VERSION 5.7 ;
  NOWIREEXTENSIONATPIN ON ;
  DIVIDERCHAR "/" ;
  BUSBITCHARS "[]" ;
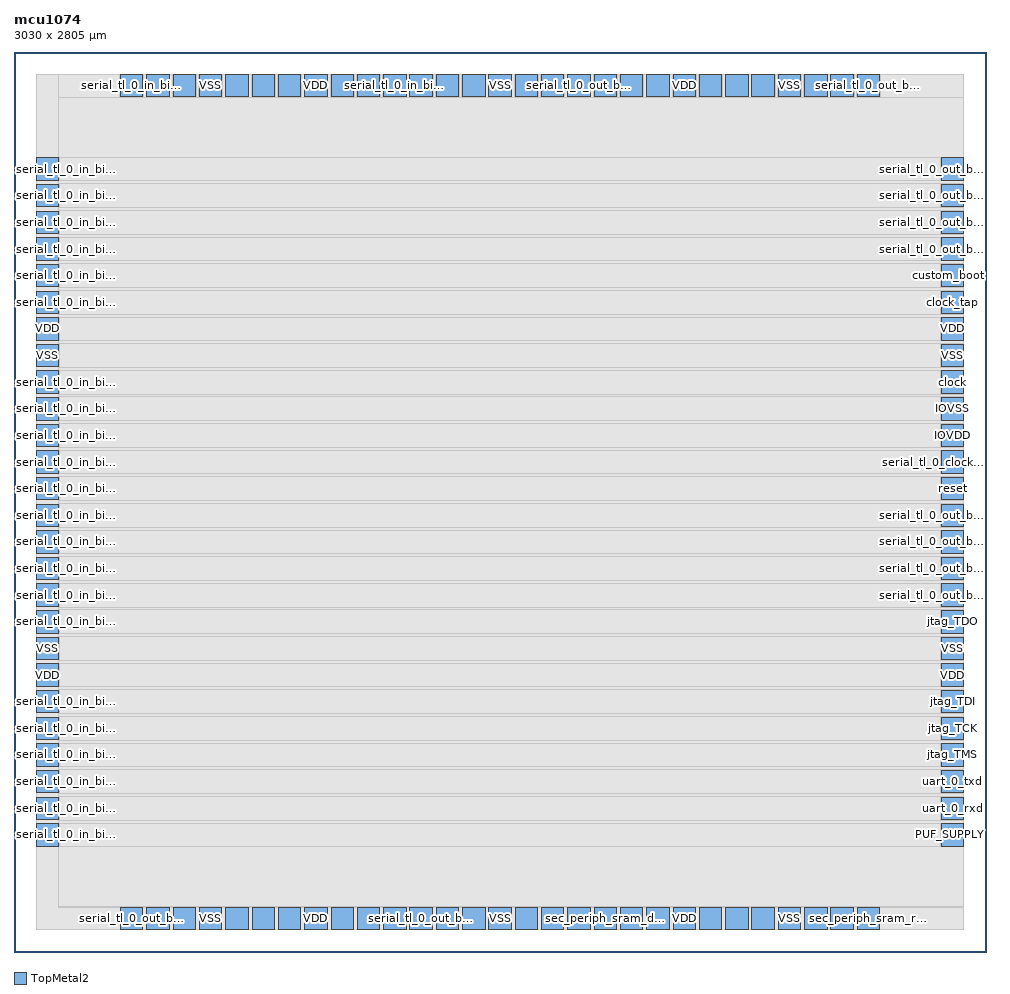
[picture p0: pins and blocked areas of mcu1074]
MACRO mcu1074
  CLASS BLOCK ;
  FOREIGN mcu1074 ;
  ORIGIN 0.000 0.000 ;
  SIZE 3030.000 BY 2805.000 ;
  PIN IOVDD
    DIRECTION INPUT ;
    USE POWER ;
    PORT
      LAYER TopMetal2 ;
        RECT 2890.000 1575.000 2960.000 1645.000 ;
    END
  END IOVDD
  PIN IOVSS
    DIRECTION INPUT ;
    USE GROUND ;
    PORT
      LAYER TopMetal2 ;
        RECT 2890.000 1658.000 2960.000 1728.000 ;
    END
  END IOVSS
  PIN PUF_SUPPLY
    DIRECTION INOUT ;
    USE POWER ;
    PORT
      LAYER TopMetal2 ;
        RECT 2890.000 330.000 2960.000 400.000 ;
    END
  END PUF_SUPPLY
  PIN VDD
    DIRECTION INPUT ;
    USE POWER ;
    PORT
      LAYER TopMetal2 ;
        RECT 70.000 1907.000 140.000 1977.000 ;
    END
  END VDD
  PIN VDD
    DIRECTION INPUT ;
    USE POWER ;
    PORT
      LAYER TopMetal2 ;
        RECT 70.000 828.000 140.000 898.000 ;
    END
  END VDD
  PIN VDD
    DIRECTION INPUT ;
    USE POWER ;
    PORT
      LAYER TopMetal2 ;
        RECT 2054.000 2665.000 2124.000 2735.000 ;
    END
  END VDD
  PIN VDD
    DIRECTION INPUT ;
    USE POWER ;
    PORT
      LAYER TopMetal2 ;
        RECT 906.000 2665.000 976.000 2735.000 ;
    END
  END VDD
  PIN VDD
    DIRECTION INPUT ;
    USE POWER ;
    PORT
      LAYER TopMetal2 ;
        RECT 2890.000 1907.000 2960.000 1977.000 ;
    END
  END VDD
  PIN VDD
    DIRECTION INPUT ;
    USE POWER ;
    PORT
      LAYER TopMetal2 ;
        RECT 2890.000 828.000 2960.000 898.000 ;
    END
  END VDD
  PIN VDD
    DIRECTION INPUT ;
    USE POWER ;
    PORT
      LAYER TopMetal2 ;
        RECT 2054.000 70.000 2124.000 140.000 ;
    END
  END VDD
  PIN VDD
    DIRECTION INPUT ;
    USE POWER ;
    PORT
      LAYER TopMetal2 ;
        RECT 906.000 70.000 976.000 140.000 ;
    END
  END VDD
  PIN VSS
    DIRECTION INPUT ;
    USE GROUND ;
    PORT
      LAYER TopMetal2 ;
        RECT 70.000 1824.000 140.000 1894.000 ;
    END
  END VSS
  PIN VSS
    DIRECTION INPUT ;
    USE GROUND ;
    PORT
      LAYER TopMetal2 ;
        RECT 70.000 911.000 140.000 981.000 ;
    END
  END VSS
  PIN VSS
    DIRECTION INPUT ;
    USE GROUND ;
    PORT
      LAYER TopMetal2 ;
        RECT 2382.000 2665.000 2452.000 2735.000 ;
    END
  END VSS
  PIN VSS
    DIRECTION INPUT ;
    USE GROUND ;
    PORT
      LAYER TopMetal2 ;
        RECT 1480.000 2665.000 1550.000 2735.000 ;
    END
  END VSS
  PIN VSS
    DIRECTION INPUT ;
    USE GROUND ;
    PORT
      LAYER TopMetal2 ;
        RECT 578.000 2665.000 648.000 2735.000 ;
    END
  END VSS
  PIN VSS
    DIRECTION INPUT ;
    USE GROUND ;
    PORT
      LAYER TopMetal2 ;
        RECT 2890.000 1824.000 2960.000 1894.000 ;
    END
  END VSS
  PIN VSS
    DIRECTION INPUT ;
    USE GROUND ;
    PORT
      LAYER TopMetal2 ;
        RECT 2890.000 911.000 2960.000 981.000 ;
    END
  END VSS
  PIN VSS
    DIRECTION INPUT ;
    USE GROUND ;
    PORT
      LAYER TopMetal2 ;
        RECT 2382.000 70.000 2452.000 140.000 ;
    END
  END VSS
  PIN VSS
    DIRECTION INPUT ;
    USE GROUND ;
    PORT
      LAYER TopMetal2 ;
        RECT 1480.000 70.000 1550.000 140.000 ;
    END
  END VSS
  PIN VSS
    DIRECTION INPUT ;
    USE GROUND ;
    PORT
      LAYER TopMetal2 ;
        RECT 578.000 70.000 648.000 140.000 ;
    END
  END VSS
  PIN clock
    DIRECTION INOUT ;
    USE SIGNAL ;
    ANTENNADIFFAREA 140.011200 ;
    PORT
      LAYER TopMetal2 ;
        RECT 2890.000 1741.000 2960.000 1811.000 ;
    END
  END clock
  PIN clock_tap
    DIRECTION INOUT ;
    USE SIGNAL ;
    ANTENNADIFFAREA 299.491180 ;
    PORT
      LAYER TopMetal2 ;
        RECT 2890.000 1990.000 2960.000 2060.000 ;
    END
  END clock_tap
  PIN custom_boot
    DIRECTION INOUT ;
    USE SIGNAL ;
    ANTENNADIFFAREA 140.011200 ;
    PORT
      LAYER TopMetal2 ;
        RECT 2890.000 2073.000 2960.000 2143.000 ;
    END
  END custom_boot
  PIN jtag_TCK
    DIRECTION INOUT ;
    USE SIGNAL ;
    ANTENNADIFFAREA 140.011200 ;
    PORT
      LAYER TopMetal2 ;
        RECT 2890.000 662.000 2960.000 732.000 ;
    END
  END jtag_TCK
  PIN jtag_TDI
    DIRECTION INOUT ;
    USE SIGNAL ;
    ANTENNADIFFAREA 140.011200 ;
    PORT
      LAYER TopMetal2 ;
        RECT 2890.000 745.000 2960.000 815.000 ;
    END
  END jtag_TDI
  PIN jtag_TDO
    DIRECTION INOUT ;
    USE SIGNAL ;
    ANTENNADIFFAREA 299.491180 ;
    PORT
      LAYER TopMetal2 ;
        RECT 2890.000 994.000 2960.000 1064.000 ;
    END
  END jtag_TDO
  PIN jtag_TMS
    DIRECTION INOUT ;
    USE SIGNAL ;
    ANTENNADIFFAREA 140.011200 ;
    PORT
      LAYER TopMetal2 ;
        RECT 2890.000 579.000 2960.000 649.000 ;
    END
  END jtag_TMS
  PIN reset
    DIRECTION INOUT ;
    USE SIGNAL ;
    ANTENNADIFFAREA 140.011200 ;
    PORT
      LAYER TopMetal2 ;
        RECT 2890.000 1409.000 2960.000 1479.000 ;
    END
  END reset
  PIN sec_periph_sram_data[0]
    DIRECTION INOUT ;
    USE SIGNAL ;
    ANTENNADIFFAREA 299.491180 ;
    PORT
      LAYER TopMetal2 ;
        RECT 2464.000 70.000 2534.000 140.000 ;
    END
  END sec_periph_sram_data[0]
  PIN sec_periph_sram_data[1]
    DIRECTION INOUT ;
    USE SIGNAL ;
    ANTENNADIFFAREA 299.491180 ;
    PORT
      LAYER TopMetal2 ;
        RECT 2300.000 70.000 2370.000 140.000 ;
    END
  END sec_periph_sram_data[1]
  PIN sec_periph_sram_data[2]
    DIRECTION INOUT ;
    USE SIGNAL ;
    ANTENNADIFFAREA 299.491180 ;
    PORT
      LAYER TopMetal2 ;
        RECT 2218.000 70.000 2288.000 140.000 ;
    END
  END sec_periph_sram_data[2]
  PIN sec_periph_sram_data[3]
    DIRECTION INOUT ;
    USE SIGNAL ;
    ANTENNADIFFAREA 299.491180 ;
    PORT
      LAYER TopMetal2 ;
        RECT 2136.000 70.000 2206.000 140.000 ;
    END
  END sec_periph_sram_data[3]
  PIN sec_periph_sram_data[4]
    DIRECTION INOUT ;
    USE SIGNAL ;
    ANTENNADIFFAREA 299.491180 ;
    PORT
      LAYER TopMetal2 ;
        RECT 1972.000 70.000 2042.000 140.000 ;
    END
  END sec_periph_sram_data[4]
  PIN sec_periph_sram_data[5]
    DIRECTION INOUT ;
    USE SIGNAL ;
    ANTENNADIFFAREA 299.491180 ;
    PORT
      LAYER TopMetal2 ;
        RECT 1890.000 70.000 1960.000 140.000 ;
    END
  END sec_periph_sram_data[5]
  PIN sec_periph_sram_data[6]
    DIRECTION INOUT ;
    USE SIGNAL ;
    ANTENNADIFFAREA 299.491180 ;
    PORT
      LAYER TopMetal2 ;
        RECT 1808.000 70.000 1878.000 140.000 ;
    END
  END sec_periph_sram_data[6]
  PIN sec_periph_sram_data[7]
    DIRECTION INOUT ;
    USE SIGNAL ;
    ANTENNADIFFAREA 299.491180 ;
    PORT
      LAYER TopMetal2 ;
        RECT 1726.000 70.000 1796.000 140.000 ;
    END
  END sec_periph_sram_data[7]
  PIN sec_periph_sram_on
    DIRECTION INOUT ;
    USE SIGNAL ;
    ANTENNADIFFAREA 299.491180 ;
    PORT
      LAYER TopMetal2 ;
        RECT 2546.000 70.000 2616.000 140.000 ;
    END
  END sec_periph_sram_on
  PIN sec_periph_sram_rdy
    DIRECTION INOUT ;
    USE SIGNAL ;
    ANTENNADIFFAREA 140.011200 ;
    PORT
      LAYER TopMetal2 ;
        RECT 2628.000 70.000 2698.000 140.000 ;
    END
  END sec_periph_sram_rdy
  PIN serial_tl_0_clock_in
    DIRECTION INOUT ;
    USE SIGNAL ;
    ANTENNADIFFAREA 140.011200 ;
    PORT
      LAYER TopMetal2 ;
        RECT 2890.000 1492.000 2960.000 1562.000 ;
    END
  END serial_tl_0_clock_in
  PIN serial_tl_0_in_bits_phit[0]
    DIRECTION INOUT ;
    USE SIGNAL ;
    ANTENNADIFFAREA 140.011200 ;
    PORT
      LAYER TopMetal2 ;
        RECT 70.000 330.000 140.000 400.000 ;
    END
  END serial_tl_0_in_bits_phit[0]
  PIN serial_tl_0_in_bits_phit[10]
    DIRECTION INOUT ;
    USE SIGNAL ;
    ANTENNADIFFAREA 140.011200 ;
    PORT
      LAYER TopMetal2 ;
        RECT 70.000 1326.000 140.000 1396.000 ;
    END
  END serial_tl_0_in_bits_phit[10]
  PIN serial_tl_0_in_bits_phit[11]
    DIRECTION INOUT ;
    USE SIGNAL ;
    ANTENNADIFFAREA 140.011200 ;
    PORT
      LAYER TopMetal2 ;
        RECT 70.000 1409.000 140.000 1479.000 ;
    END
  END serial_tl_0_in_bits_phit[11]
  PIN serial_tl_0_in_bits_phit[12]
    DIRECTION INOUT ;
    USE SIGNAL ;
    ANTENNADIFFAREA 140.011200 ;
    PORT
      LAYER TopMetal2 ;
        RECT 70.000 1492.000 140.000 1562.000 ;
    END
  END serial_tl_0_in_bits_phit[12]
  PIN serial_tl_0_in_bits_phit[13]
    DIRECTION INOUT ;
    USE SIGNAL ;
    ANTENNADIFFAREA 140.011200 ;
    PORT
      LAYER TopMetal2 ;
        RECT 70.000 1575.000 140.000 1645.000 ;
    END
  END serial_tl_0_in_bits_phit[13]
  PIN serial_tl_0_in_bits_phit[14]
    DIRECTION INOUT ;
    USE SIGNAL ;
    ANTENNADIFFAREA 140.011200 ;
    PORT
      LAYER TopMetal2 ;
        RECT 70.000 1658.000 140.000 1728.000 ;
    END
  END serial_tl_0_in_bits_phit[14]
  PIN serial_tl_0_in_bits_phit[15]
    DIRECTION INOUT ;
    USE SIGNAL ;
    ANTENNADIFFAREA 140.011200 ;
    PORT
      LAYER TopMetal2 ;
        RECT 70.000 1741.000 140.000 1811.000 ;
    END
  END serial_tl_0_in_bits_phit[15]
  PIN serial_tl_0_in_bits_phit[16]
    DIRECTION INOUT ;
    USE SIGNAL ;
    ANTENNADIFFAREA 140.011200 ;
    PORT
      LAYER TopMetal2 ;
        RECT 70.000 1990.000 140.000 2060.000 ;
    END
  END serial_tl_0_in_bits_phit[16]
  PIN serial_tl_0_in_bits_phit[17]
    DIRECTION INOUT ;
    USE SIGNAL ;
    ANTENNADIFFAREA 140.011200 ;
    PORT
      LAYER TopMetal2 ;
        RECT 70.000 2073.000 140.000 2143.000 ;
    END
  END serial_tl_0_in_bits_phit[17]
  PIN serial_tl_0_in_bits_phit[18]
    DIRECTION INOUT ;
    USE SIGNAL ;
    ANTENNADIFFAREA 140.011200 ;
    PORT
      LAYER TopMetal2 ;
        RECT 70.000 2156.000 140.000 2226.000 ;
    END
  END serial_tl_0_in_bits_phit[18]
  PIN serial_tl_0_in_bits_phit[19]
    DIRECTION INOUT ;
    USE SIGNAL ;
    ANTENNADIFFAREA 140.011200 ;
    PORT
      LAYER TopMetal2 ;
        RECT 70.000 2239.000 140.000 2309.000 ;
    END
  END serial_tl_0_in_bits_phit[19]
  PIN serial_tl_0_in_bits_phit[1]
    DIRECTION INOUT ;
    USE SIGNAL ;
    ANTENNADIFFAREA 140.011200 ;
    PORT
      LAYER TopMetal2 ;
        RECT 70.000 413.000 140.000 483.000 ;
    END
  END serial_tl_0_in_bits_phit[1]
  PIN serial_tl_0_in_bits_phit[20]
    DIRECTION INOUT ;
    USE SIGNAL ;
    ANTENNADIFFAREA 140.011200 ;
    PORT
      LAYER TopMetal2 ;
        RECT 70.000 2322.000 140.000 2392.000 ;
    END
  END serial_tl_0_in_bits_phit[20]
  PIN serial_tl_0_in_bits_phit[21]
    DIRECTION INOUT ;
    USE SIGNAL ;
    ANTENNADIFFAREA 140.011200 ;
    PORT
      LAYER TopMetal2 ;
        RECT 70.000 2405.000 140.000 2475.000 ;
    END
  END serial_tl_0_in_bits_phit[21]
  PIN serial_tl_0_in_bits_phit[22]
    DIRECTION INOUT ;
    USE SIGNAL ;
    ANTENNADIFFAREA 140.011200 ;
    PORT
      LAYER TopMetal2 ;
        RECT 332.000 2665.000 402.000 2735.000 ;
    END
  END serial_tl_0_in_bits_phit[22]
  PIN serial_tl_0_in_bits_phit[23]
    DIRECTION INOUT ;
    USE SIGNAL ;
    ANTENNADIFFAREA 140.011200 ;
    PORT
      LAYER TopMetal2 ;
        RECT 414.000 2665.000 484.000 2735.000 ;
    END
  END serial_tl_0_in_bits_phit[23]
  PIN serial_tl_0_in_bits_phit[24]
    DIRECTION INOUT ;
    USE SIGNAL ;
    ANTENNADIFFAREA 140.011200 ;
    PORT
      LAYER TopMetal2 ;
        RECT 496.000 2665.000 566.000 2735.000 ;
    END
  END serial_tl_0_in_bits_phit[24]
  PIN serial_tl_0_in_bits_phit[25]
    DIRECTION INOUT ;
    USE SIGNAL ;
    ANTENNADIFFAREA 140.011200 ;
    PORT
      LAYER TopMetal2 ;
        RECT 660.000 2665.000 730.000 2735.000 ;
    END
  END serial_tl_0_in_bits_phit[25]
  PIN serial_tl_0_in_bits_phit[26]
    DIRECTION INOUT ;
    USE SIGNAL ;
    ANTENNADIFFAREA 140.011200 ;
    PORT
      LAYER TopMetal2 ;
        RECT 742.000 2665.000 812.000 2735.000 ;
    END
  END serial_tl_0_in_bits_phit[26]
  PIN serial_tl_0_in_bits_phit[27]
    DIRECTION INOUT ;
    USE SIGNAL ;
    ANTENNADIFFAREA 140.011200 ;
    PORT
      LAYER TopMetal2 ;
        RECT 824.000 2665.000 894.000 2735.000 ;
    END
  END serial_tl_0_in_bits_phit[27]
  PIN serial_tl_0_in_bits_phit[28]
    DIRECTION INOUT ;
    USE SIGNAL ;
    ANTENNADIFFAREA 140.011200 ;
    PORT
      LAYER TopMetal2 ;
        RECT 988.000 2665.000 1058.000 2735.000 ;
    END
  END serial_tl_0_in_bits_phit[28]
  PIN serial_tl_0_in_bits_phit[29]
    DIRECTION INOUT ;
    USE SIGNAL ;
    ANTENNADIFFAREA 140.011200 ;
    PORT
      LAYER TopMetal2 ;
        RECT 1070.000 2665.000 1140.000 2735.000 ;
    END
  END serial_tl_0_in_bits_phit[29]
  PIN serial_tl_0_in_bits_phit[2]
    DIRECTION INOUT ;
    USE SIGNAL ;
    ANTENNADIFFAREA 140.011200 ;
    PORT
      LAYER TopMetal2 ;
        RECT 70.000 496.000 140.000 566.000 ;
    END
  END serial_tl_0_in_bits_phit[2]
  PIN serial_tl_0_in_bits_phit[30]
    DIRECTION INOUT ;
    USE SIGNAL ;
    ANTENNADIFFAREA 140.011200 ;
    PORT
      LAYER TopMetal2 ;
        RECT 1152.000 2665.000 1222.000 2735.000 ;
    END
  END serial_tl_0_in_bits_phit[30]
  PIN serial_tl_0_in_bits_phit[31]
    DIRECTION INOUT ;
    USE SIGNAL ;
    ANTENNADIFFAREA 140.011200 ;
    PORT
      LAYER TopMetal2 ;
        RECT 1234.000 2665.000 1304.000 2735.000 ;
    END
  END serial_tl_0_in_bits_phit[31]
  PIN serial_tl_0_in_bits_phit[3]
    DIRECTION INOUT ;
    USE SIGNAL ;
    ANTENNADIFFAREA 140.011200 ;
    PORT
      LAYER TopMetal2 ;
        RECT 70.000 579.000 140.000 649.000 ;
    END
  END serial_tl_0_in_bits_phit[3]
  PIN serial_tl_0_in_bits_phit[4]
    DIRECTION INOUT ;
    USE SIGNAL ;
    ANTENNADIFFAREA 140.011200 ;
    PORT
      LAYER TopMetal2 ;
        RECT 70.000 662.000 140.000 732.000 ;
    END
  END serial_tl_0_in_bits_phit[4]
  PIN serial_tl_0_in_bits_phit[5]
    DIRECTION INOUT ;
    USE SIGNAL ;
    ANTENNADIFFAREA 140.011200 ;
    PORT
      LAYER TopMetal2 ;
        RECT 70.000 745.000 140.000 815.000 ;
    END
  END serial_tl_0_in_bits_phit[5]
  PIN serial_tl_0_in_bits_phit[6]
    DIRECTION INOUT ;
    USE SIGNAL ;
    ANTENNADIFFAREA 140.011200 ;
    PORT
      LAYER TopMetal2 ;
        RECT 70.000 994.000 140.000 1064.000 ;
    END
  END serial_tl_0_in_bits_phit[6]
  PIN serial_tl_0_in_bits_phit[7]
    DIRECTION INOUT ;
    USE SIGNAL ;
    ANTENNADIFFAREA 140.011200 ;
    PORT
      LAYER TopMetal2 ;
        RECT 70.000 1077.000 140.000 1147.000 ;
    END
  END serial_tl_0_in_bits_phit[7]
  PIN serial_tl_0_in_bits_phit[8]
    DIRECTION INOUT ;
    USE SIGNAL ;
    ANTENNADIFFAREA 140.011200 ;
    PORT
      LAYER TopMetal2 ;
        RECT 70.000 1160.000 140.000 1230.000 ;
    END
  END serial_tl_0_in_bits_phit[8]
  PIN serial_tl_0_in_bits_phit[9]
    DIRECTION INOUT ;
    USE SIGNAL ;
    ANTENNADIFFAREA 140.011200 ;
    PORT
      LAYER TopMetal2 ;
        RECT 70.000 1243.000 140.000 1313.000 ;
    END
  END serial_tl_0_in_bits_phit[9]
  PIN serial_tl_0_in_ready
    DIRECTION INOUT ;
    USE SIGNAL ;
    ANTENNADIFFAREA 299.491180 ;
    PORT
      LAYER TopMetal2 ;
        RECT 1316.000 2665.000 1386.000 2735.000 ;
    END
  END serial_tl_0_in_ready
  PIN serial_tl_0_in_valid
    DIRECTION INOUT ;
    USE SIGNAL ;
    ANTENNADIFFAREA 140.011200 ;
    PORT
      LAYER TopMetal2 ;
        RECT 1398.000 2665.000 1468.000 2735.000 ;
    END
  END serial_tl_0_in_valid
  PIN serial_tl_0_out_bits_phit[0]
    DIRECTION INOUT ;
    USE SIGNAL ;
    ANTENNADIFFAREA 299.491180 ;
    PORT
      LAYER TopMetal2 ;
        RECT 1726.000 2665.000 1796.000 2735.000 ;
    END
  END serial_tl_0_out_bits_phit[0]
  PIN serial_tl_0_out_bits_phit[10]
    DIRECTION INOUT ;
    USE SIGNAL ;
    ANTENNADIFFAREA 299.491180 ;
    PORT
      LAYER TopMetal2 ;
        RECT 2890.000 2405.000 2960.000 2475.000 ;
    END
  END serial_tl_0_out_bits_phit[10]
  PIN serial_tl_0_out_bits_phit[11]
    DIRECTION INOUT ;
    USE SIGNAL ;
    ANTENNADIFFAREA 299.491180 ;
    PORT
      LAYER TopMetal2 ;
        RECT 2890.000 2322.000 2960.000 2392.000 ;
    END
  END serial_tl_0_out_bits_phit[11]
  PIN serial_tl_0_out_bits_phit[12]
    DIRECTION INOUT ;
    USE SIGNAL ;
    ANTENNADIFFAREA 299.491180 ;
    PORT
      LAYER TopMetal2 ;
        RECT 2890.000 2239.000 2960.000 2309.000 ;
    END
  END serial_tl_0_out_bits_phit[12]
  PIN serial_tl_0_out_bits_phit[13]
    DIRECTION INOUT ;
    USE SIGNAL ;
    ANTENNADIFFAREA 299.491180 ;
    PORT
      LAYER TopMetal2 ;
        RECT 2890.000 2156.000 2960.000 2226.000 ;
    END
  END serial_tl_0_out_bits_phit[13]
  PIN serial_tl_0_out_bits_phit[14]
    DIRECTION INOUT ;
    USE SIGNAL ;
    ANTENNADIFFAREA 299.491180 ;
    PORT
      LAYER TopMetal2 ;
        RECT 2890.000 1326.000 2960.000 1396.000 ;
    END
  END serial_tl_0_out_bits_phit[14]
  PIN serial_tl_0_out_bits_phit[15]
    DIRECTION INOUT ;
    USE SIGNAL ;
    ANTENNADIFFAREA 299.491180 ;
    PORT
      LAYER TopMetal2 ;
        RECT 2890.000 1243.000 2960.000 1313.000 ;
    END
  END serial_tl_0_out_bits_phit[15]
  PIN serial_tl_0_out_bits_phit[16]
    DIRECTION INOUT ;
    USE SIGNAL ;
    ANTENNADIFFAREA 299.491180 ;
    PORT
      LAYER TopMetal2 ;
        RECT 2890.000 1160.000 2960.000 1230.000 ;
    END
  END serial_tl_0_out_bits_phit[16]
  PIN serial_tl_0_out_bits_phit[17]
    DIRECTION INOUT ;
    USE SIGNAL ;
    ANTENNADIFFAREA 299.491180 ;
    PORT
      LAYER TopMetal2 ;
        RECT 2890.000 1077.000 2960.000 1147.000 ;
    END
  END serial_tl_0_out_bits_phit[17]
  PIN serial_tl_0_out_bits_phit[18]
    DIRECTION INOUT ;
    USE SIGNAL ;
    ANTENNADIFFAREA 299.491180 ;
    PORT
      LAYER TopMetal2 ;
        RECT 1644.000 70.000 1714.000 140.000 ;
    END
  END serial_tl_0_out_bits_phit[18]
  PIN serial_tl_0_out_bits_phit[19]
    DIRECTION INOUT ;
    USE SIGNAL ;
    ANTENNADIFFAREA 299.491180 ;
    PORT
      LAYER TopMetal2 ;
        RECT 1562.000 70.000 1632.000 140.000 ;
    END
  END serial_tl_0_out_bits_phit[19]
  PIN serial_tl_0_out_bits_phit[1]
    DIRECTION INOUT ;
    USE SIGNAL ;
    ANTENNADIFFAREA 299.491180 ;
    PORT
      LAYER TopMetal2 ;
        RECT 1808.000 2665.000 1878.000 2735.000 ;
    END
  END serial_tl_0_out_bits_phit[1]
  PIN serial_tl_0_out_bits_phit[20]
    DIRECTION INOUT ;
    USE SIGNAL ;
    ANTENNADIFFAREA 299.491180 ;
    PORT
      LAYER TopMetal2 ;
        RECT 1398.000 70.000 1468.000 140.000 ;
    END
  END serial_tl_0_out_bits_phit[20]
  PIN serial_tl_0_out_bits_phit[21]
    DIRECTION INOUT ;
    USE SIGNAL ;
    ANTENNADIFFAREA 299.491180 ;
    PORT
      LAYER TopMetal2 ;
        RECT 1316.000 70.000 1386.000 140.000 ;
    END
  END serial_tl_0_out_bits_phit[21]
  PIN serial_tl_0_out_bits_phit[22]
    DIRECTION INOUT ;
    USE SIGNAL ;
    ANTENNADIFFAREA 299.491180 ;
    PORT
      LAYER TopMetal2 ;
        RECT 1234.000 70.000 1304.000 140.000 ;
    END
  END serial_tl_0_out_bits_phit[22]
  PIN serial_tl_0_out_bits_phit[23]
    DIRECTION INOUT ;
    USE SIGNAL ;
    ANTENNADIFFAREA 299.491180 ;
    PORT
      LAYER TopMetal2 ;
        RECT 1152.000 70.000 1222.000 140.000 ;
    END
  END serial_tl_0_out_bits_phit[23]
  PIN serial_tl_0_out_bits_phit[24]
    DIRECTION INOUT ;
    USE SIGNAL ;
    ANTENNADIFFAREA 299.491180 ;
    PORT
      LAYER TopMetal2 ;
        RECT 1070.000 70.000 1140.000 140.000 ;
    END
  END serial_tl_0_out_bits_phit[24]
  PIN serial_tl_0_out_bits_phit[25]
    DIRECTION INOUT ;
    USE SIGNAL ;
    ANTENNADIFFAREA 299.491180 ;
    PORT
      LAYER TopMetal2 ;
        RECT 988.000 70.000 1058.000 140.000 ;
    END
  END serial_tl_0_out_bits_phit[25]
  PIN serial_tl_0_out_bits_phit[26]
    DIRECTION INOUT ;
    USE SIGNAL ;
    ANTENNADIFFAREA 299.491180 ;
    PORT
      LAYER TopMetal2 ;
        RECT 824.000 70.000 894.000 140.000 ;
    END
  END serial_tl_0_out_bits_phit[26]
  PIN serial_tl_0_out_bits_phit[27]
    DIRECTION INOUT ;
    USE SIGNAL ;
    ANTENNADIFFAREA 299.491180 ;
    PORT
      LAYER TopMetal2 ;
        RECT 742.000 70.000 812.000 140.000 ;
    END
  END serial_tl_0_out_bits_phit[27]
  PIN serial_tl_0_out_bits_phit[28]
    DIRECTION INOUT ;
    USE SIGNAL ;
    ANTENNADIFFAREA 299.491180 ;
    PORT
      LAYER TopMetal2 ;
        RECT 660.000 70.000 730.000 140.000 ;
    END
  END serial_tl_0_out_bits_phit[28]
  PIN serial_tl_0_out_bits_phit[29]
    DIRECTION INOUT ;
    USE SIGNAL ;
    ANTENNADIFFAREA 299.491180 ;
    PORT
      LAYER TopMetal2 ;
        RECT 496.000 70.000 566.000 140.000 ;
    END
  END serial_tl_0_out_bits_phit[29]
  PIN serial_tl_0_out_bits_phit[2]
    DIRECTION INOUT ;
    USE SIGNAL ;
    ANTENNADIFFAREA 299.491180 ;
    PORT
      LAYER TopMetal2 ;
        RECT 1890.000 2665.000 1960.000 2735.000 ;
    END
  END serial_tl_0_out_bits_phit[2]
  PIN serial_tl_0_out_bits_phit[30]
    DIRECTION INOUT ;
    USE SIGNAL ;
    ANTENNADIFFAREA 299.491180 ;
    PORT
      LAYER TopMetal2 ;
        RECT 414.000 70.000 484.000 140.000 ;
    END
  END serial_tl_0_out_bits_phit[30]
  PIN serial_tl_0_out_bits_phit[31]
    DIRECTION INOUT ;
    USE SIGNAL ;
    ANTENNADIFFAREA 299.491180 ;
    PORT
      LAYER TopMetal2 ;
        RECT 332.000 70.000 402.000 140.000 ;
    END
  END serial_tl_0_out_bits_phit[31]
  PIN serial_tl_0_out_bits_phit[3]
    DIRECTION INOUT ;
    USE SIGNAL ;
    ANTENNADIFFAREA 299.491180 ;
    PORT
      LAYER TopMetal2 ;
        RECT 1972.000 2665.000 2042.000 2735.000 ;
    END
  END serial_tl_0_out_bits_phit[3]
  PIN serial_tl_0_out_bits_phit[4]
    DIRECTION INOUT ;
    USE SIGNAL ;
    ANTENNADIFFAREA 299.491180 ;
    PORT
      LAYER TopMetal2 ;
        RECT 2136.000 2665.000 2206.000 2735.000 ;
    END
  END serial_tl_0_out_bits_phit[4]
  PIN serial_tl_0_out_bits_phit[5]
    DIRECTION INOUT ;
    USE SIGNAL ;
    ANTENNADIFFAREA 299.491180 ;
    PORT
      LAYER TopMetal2 ;
        RECT 2218.000 2665.000 2288.000 2735.000 ;
    END
  END serial_tl_0_out_bits_phit[5]
  PIN serial_tl_0_out_bits_phit[6]
    DIRECTION INOUT ;
    USE SIGNAL ;
    ANTENNADIFFAREA 299.491180 ;
    PORT
      LAYER TopMetal2 ;
        RECT 2300.000 2665.000 2370.000 2735.000 ;
    END
  END serial_tl_0_out_bits_phit[6]
  PIN serial_tl_0_out_bits_phit[7]
    DIRECTION INOUT ;
    USE SIGNAL ;
    ANTENNADIFFAREA 299.491180 ;
    PORT
      LAYER TopMetal2 ;
        RECT 2464.000 2665.000 2534.000 2735.000 ;
    END
  END serial_tl_0_out_bits_phit[7]
  PIN serial_tl_0_out_bits_phit[8]
    DIRECTION INOUT ;
    USE SIGNAL ;
    ANTENNADIFFAREA 299.491180 ;
    PORT
      LAYER TopMetal2 ;
        RECT 2546.000 2665.000 2616.000 2735.000 ;
    END
  END serial_tl_0_out_bits_phit[8]
  PIN serial_tl_0_out_bits_phit[9]
    DIRECTION INOUT ;
    USE SIGNAL ;
    ANTENNADIFFAREA 299.491180 ;
    PORT
      LAYER TopMetal2 ;
        RECT 2628.000 2665.000 2698.000 2735.000 ;
    END
  END serial_tl_0_out_bits_phit[9]
  PIN serial_tl_0_out_ready
    DIRECTION INOUT ;
    USE SIGNAL ;
    ANTENNADIFFAREA 140.011200 ;
    PORT
      LAYER TopMetal2 ;
        RECT 1644.000 2665.000 1714.000 2735.000 ;
    END
  END serial_tl_0_out_ready
  PIN serial_tl_0_out_valid
    DIRECTION INOUT ;
    USE SIGNAL ;
    ANTENNADIFFAREA 299.491180 ;
    PORT
      LAYER TopMetal2 ;
        RECT 1562.000 2665.000 1632.000 2735.000 ;
    END
  END serial_tl_0_out_valid
  PIN uart_0_rxd
    DIRECTION INOUT ;
    USE SIGNAL ;
    ANTENNADIFFAREA 140.011200 ;
    PORT
      LAYER TopMetal2 ;
        RECT 2890.000 413.000 2960.000 483.000 ;
    END
  END uart_0_rxd
  PIN uart_0_txd
    DIRECTION INOUT ;
    USE SIGNAL ;
    ANTENNADIFFAREA 299.491180 ;
    PORT
      LAYER TopMetal2 ;
        RECT 2890.000 496.000 2960.000 566.000 ;
    END
  END uart_0_txd
  OBS
      LAYER GatPoly ;
        RECT 146.000 146.000 2884.000 2659.000 ;
      LAYER Metal1 ;
        RECT 146.000 146.000 2884.000 2659.000 ;
      LAYER Metal2 ;
        RECT 70.000 70.000 2960.005 2735.005 ;
      LAYER Metal3 ;
        RECT 70.000 70.000 2960.005 2735.005 ;
      LAYER Metal4 ;
        RECT 70.000 70.000 2960.005 2735.005 ;
      LAYER Metal5 ;
        RECT 70.000 70.000 2960.005 2735.005 ;
      LAYER TopMetal1 ;
        RECT 70.000 70.000 2960.005 2735.005 ;
      LAYER TopMetal2 ;
        RECT 140.000 2663.000 330.000 2735.005 ;
        RECT 404.000 2663.000 412.000 2735.005 ;
        RECT 486.000 2663.000 494.000 2735.005 ;
        RECT 568.000 2663.000 576.000 2735.005 ;
        RECT 650.000 2663.000 658.000 2735.005 ;
        RECT 732.000 2663.000 740.000 2735.005 ;
        RECT 814.000 2663.000 822.000 2735.005 ;
        RECT 896.000 2663.000 904.000 2735.005 ;
        RECT 978.000 2663.000 986.000 2735.005 ;
        RECT 1060.000 2663.000 1068.000 2735.005 ;
        RECT 1142.000 2663.000 1150.000 2735.005 ;
        RECT 1224.000 2663.000 1232.000 2735.005 ;
        RECT 1306.000 2663.000 1314.000 2735.005 ;
        RECT 1388.000 2663.000 1396.000 2735.005 ;
        RECT 1470.000 2663.000 1478.000 2735.005 ;
        RECT 1552.000 2663.000 1560.000 2735.005 ;
        RECT 1634.000 2663.000 1642.000 2735.005 ;
        RECT 1716.000 2663.000 1724.000 2735.005 ;
        RECT 1798.000 2663.000 1806.000 2735.005 ;
        RECT 1880.000 2663.000 1888.000 2735.005 ;
        RECT 1962.000 2663.000 1970.000 2735.005 ;
        RECT 2044.000 2663.000 2052.000 2735.005 ;
        RECT 2126.000 2663.000 2134.000 2735.005 ;
        RECT 2208.000 2663.000 2216.000 2735.005 ;
        RECT 2290.000 2663.000 2298.000 2735.005 ;
        RECT 2372.000 2663.000 2380.000 2735.005 ;
        RECT 2454.000 2663.000 2462.000 2735.005 ;
        RECT 2536.000 2663.000 2544.000 2735.005 ;
        RECT 2618.000 2663.000 2626.000 2735.005 ;
        RECT 2700.000 2663.000 2960.005 2735.005 ;
        RECT 140.000 2477.000 2960.005 2663.000 ;
        RECT 142.000 2403.000 2888.000 2477.000 ;
        RECT 140.000 2394.000 2960.005 2403.000 ;
        RECT 142.000 2320.000 2888.000 2394.000 ;
        RECT 140.000 2311.000 2960.005 2320.000 ;
        RECT 142.000 2237.000 2888.000 2311.000 ;
        RECT 140.000 2228.000 2960.005 2237.000 ;
        RECT 142.000 2154.000 2888.000 2228.000 ;
        RECT 140.000 2145.000 2960.005 2154.000 ;
        RECT 142.000 2071.000 2888.000 2145.000 ;
        RECT 140.000 2062.000 2960.005 2071.000 ;
        RECT 142.000 1988.000 2888.000 2062.000 ;
        RECT 140.000 1979.000 2960.005 1988.000 ;
        RECT 142.000 1905.000 2888.000 1979.000 ;
        RECT 140.000 1896.000 2960.005 1905.000 ;
        RECT 142.000 1822.000 2888.000 1896.000 ;
        RECT 140.000 1813.000 2960.005 1822.000 ;
        RECT 142.000 1739.000 2888.000 1813.000 ;
        RECT 140.000 1730.000 2960.005 1739.000 ;
        RECT 142.000 1656.000 2888.000 1730.000 ;
        RECT 140.000 1647.000 2960.005 1656.000 ;
        RECT 142.000 1573.000 2888.000 1647.000 ;
        RECT 140.000 1564.000 2960.005 1573.000 ;
        RECT 142.000 1490.000 2888.000 1564.000 ;
        RECT 140.000 1481.000 2960.005 1490.000 ;
        RECT 142.000 1407.000 2888.000 1481.000 ;
        RECT 140.000 1398.000 2960.005 1407.000 ;
        RECT 142.000 1324.000 2888.000 1398.000 ;
        RECT 140.000 1315.000 2960.005 1324.000 ;
        RECT 142.000 1241.000 2888.000 1315.000 ;
        RECT 140.000 1232.000 2960.005 1241.000 ;
        RECT 142.000 1158.000 2888.000 1232.000 ;
        RECT 140.000 1149.000 2960.005 1158.000 ;
        RECT 142.000 1075.000 2888.000 1149.000 ;
        RECT 140.000 1066.000 2960.005 1075.000 ;
        RECT 142.000 992.000 2888.000 1066.000 ;
        RECT 140.000 983.000 2960.005 992.000 ;
        RECT 142.000 909.000 2888.000 983.000 ;
        RECT 140.000 900.000 2960.005 909.000 ;
        RECT 142.000 826.000 2888.000 900.000 ;
        RECT 140.000 817.000 2960.005 826.000 ;
        RECT 142.000 743.000 2888.000 817.000 ;
        RECT 140.000 734.000 2960.005 743.000 ;
        RECT 142.000 660.000 2888.000 734.000 ;
        RECT 140.000 651.000 2960.005 660.000 ;
        RECT 142.000 577.000 2888.000 651.000 ;
        RECT 140.000 568.000 2960.005 577.000 ;
        RECT 142.000 494.000 2888.000 568.000 ;
        RECT 140.000 485.000 2960.005 494.000 ;
        RECT 142.000 411.000 2888.000 485.000 ;
        RECT 140.000 402.000 2960.005 411.000 ;
        RECT 142.000 328.000 2888.000 402.000 ;
        RECT 140.000 142.000 2960.005 328.000 ;
        RECT 140.000 140.000 330.000 142.000 ;
        RECT 404.000 140.000 412.000 142.000 ;
        RECT 486.000 140.000 494.000 142.000 ;
        RECT 568.000 140.000 576.000 142.000 ;
        RECT 650.000 140.000 658.000 142.000 ;
        RECT 732.000 140.000 740.000 142.000 ;
        RECT 814.000 140.000 822.000 142.000 ;
        RECT 896.000 140.000 904.000 142.000 ;
        RECT 978.000 140.000 986.000 142.000 ;
        RECT 1060.000 140.000 1068.000 142.000 ;
        RECT 1142.000 140.000 1150.000 142.000 ;
        RECT 1224.000 140.000 1232.000 142.000 ;
        RECT 1306.000 140.000 1314.000 142.000 ;
        RECT 1388.000 140.000 1396.000 142.000 ;
        RECT 1470.000 140.000 1478.000 142.000 ;
        RECT 1552.000 140.000 1560.000 142.000 ;
        RECT 1634.000 140.000 1642.000 142.000 ;
        RECT 1716.000 140.000 1724.000 142.000 ;
        RECT 1798.000 140.000 1806.000 142.000 ;
        RECT 1880.000 140.000 1888.000 142.000 ;
        RECT 1962.000 140.000 1970.000 142.000 ;
        RECT 2044.000 140.000 2052.000 142.000 ;
        RECT 2126.000 140.000 2134.000 142.000 ;
        RECT 2208.000 140.000 2216.000 142.000 ;
        RECT 2290.000 140.000 2298.000 142.000 ;
        RECT 2372.000 140.000 2380.000 142.000 ;
        RECT 2454.000 140.000 2462.000 142.000 ;
        RECT 2536.000 140.000 2544.000 142.000 ;
        RECT 2618.000 140.000 2626.000 142.000 ;
        RECT 2700.000 140.000 2960.005 142.000 ;
  END
END mcu1074
END LIBRARY

